One B-rep face of a CAD part: STEP entity #432.
In plain terms, the planar face has unit normal (1, 0, 0).
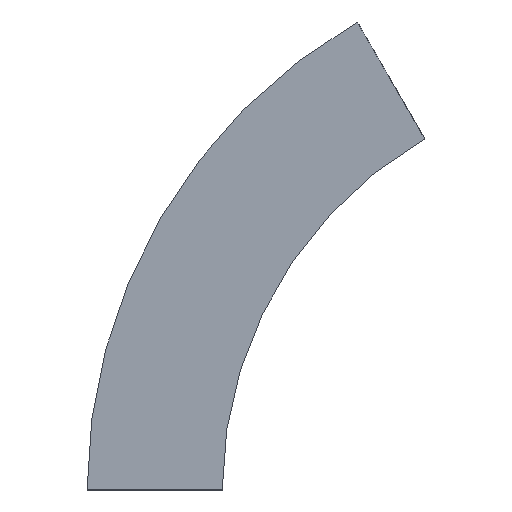
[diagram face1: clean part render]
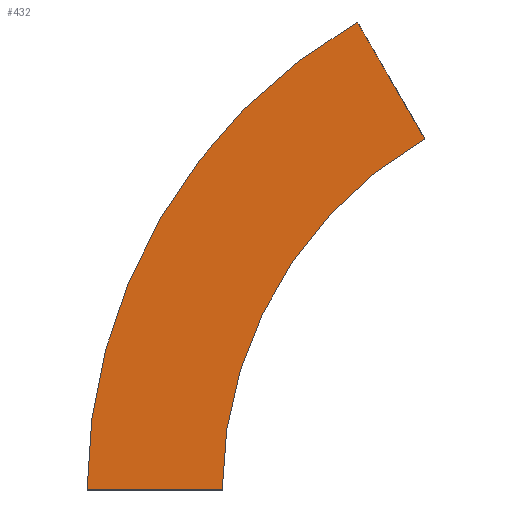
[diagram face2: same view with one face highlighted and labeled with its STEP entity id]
Its self-contained STEP definition (entity closure, numbers rounded to 3 decimals):
#10 = CARTESIAN_POINT ( 'NONE',  ( 0., -100., 346.41 ) ) ;
#22 = CARTESIAN_POINT ( 'NONE',  ( 0., -300., 0. ) ) ;
#45 = EDGE_CURVE ( 'NONE', #160, #475, #465, .T. ) ;
#55 = VECTOR ( 'NONE', #302, 1000. ) ;
#77 = DIRECTION ( 'NONE',  ( 0., 1., 0. ) ) ;
#79 = DIRECTION ( 'NONE',  ( 0., 1., 0. ) ) ;
#98 = DIRECTION ( 'NONE',  ( 1., 0., 0. ) ) ;
#108 = VERTEX_POINT ( 'NONE', #161 ) ;
#113 = EDGE_CURVE ( 'NONE', #108, #301, #379, .T. ) ;
#117 = AXIS2_PLACEMENT_3D ( 'NONE', #482, #98, #181 ) ;
#127 = DIRECTION ( 'NONE',  ( 1., 0., 0. ) ) ;
#160 = VERTEX_POINT ( 'NONE', #528 ) ;
#161 = CARTESIAN_POINT ( 'NONE',  ( 0., 100., 0. ) ) ;
#181 = DIRECTION ( 'NONE',  ( 0., 0., -1. ) ) ;
#189 = CARTESIAN_POINT ( 'NONE',  ( 0., -150., 259.808 ) ) ;
#198 = DIRECTION ( 'NONE',  ( 1., 0., 0. ) ) ;
#213 = AXIS2_PLACEMENT_3D ( 'NONE', #22, #198, #77 ) ;
#215 = CARTESIAN_POINT ( 'NONE',  ( 0., 0., 0. ) ) ;
#301 = VERTEX_POINT ( 'NONE', #10 ) ;
#302 = DIRECTION ( 'NONE',  ( 0., 1., 0. ) ) ;
#308 = PLANE ( 'NONE',  #117 ) ;
#309 = ORIENTED_EDGE ( 'NONE', *, *, #420, .T. ) ;
#335 = LINE ( 'NONE', #215, #55 ) ;
#354 = VECTOR ( 'NONE', #490, 1000. ) ;
#379 = CIRCLE ( 'NONE', #391, 400. ) ;
#380 = ORIENTED_EDGE ( 'NONE', *, *, #45, .F. ) ;
#389 = FACE_OUTER_BOUND ( 'NONE', #429, .T. ) ;
#391 = AXIS2_PLACEMENT_3D ( 'NONE', #469, #127, #79 ) ;
#420 = EDGE_CURVE ( 'NONE', #160, #108, #335, .T. ) ;
#429 = EDGE_LOOP ( 'NONE', ( #496, #453, #380, #309 ) ) ;
#432 = ADVANCED_FACE ( 'NONE', ( #389 ), #308, .T. ) ;
#453 = ORIENTED_EDGE ( 'NONE', *, *, #566, .F. ) ;
#464 = LINE ( 'NONE', #189, #354 ) ;
#465 = CIRCLE ( 'NONE', #213, 300. ) ;
#469 = CARTESIAN_POINT ( 'NONE',  ( 0., -300., 0. ) ) ;
#475 = VERTEX_POINT ( 'NONE', #483 ) ;
#482 = CARTESIAN_POINT ( 'NONE',  ( 0., 0., 0. ) ) ;
#483 = CARTESIAN_POINT ( 'NONE',  ( 0., -150., 259.808 ) ) ;
#490 = DIRECTION ( 'NONE',  ( 0., 0.5, 0.866 ) ) ;
#496 = ORIENTED_EDGE ( 'NONE', *, *, #113, .T. ) ;
#528 = CARTESIAN_POINT ( 'NONE',  ( 0., 0., 0. ) ) ;
#566 = EDGE_CURVE ( 'NONE', #475, #301, #464, .T. ) ;
